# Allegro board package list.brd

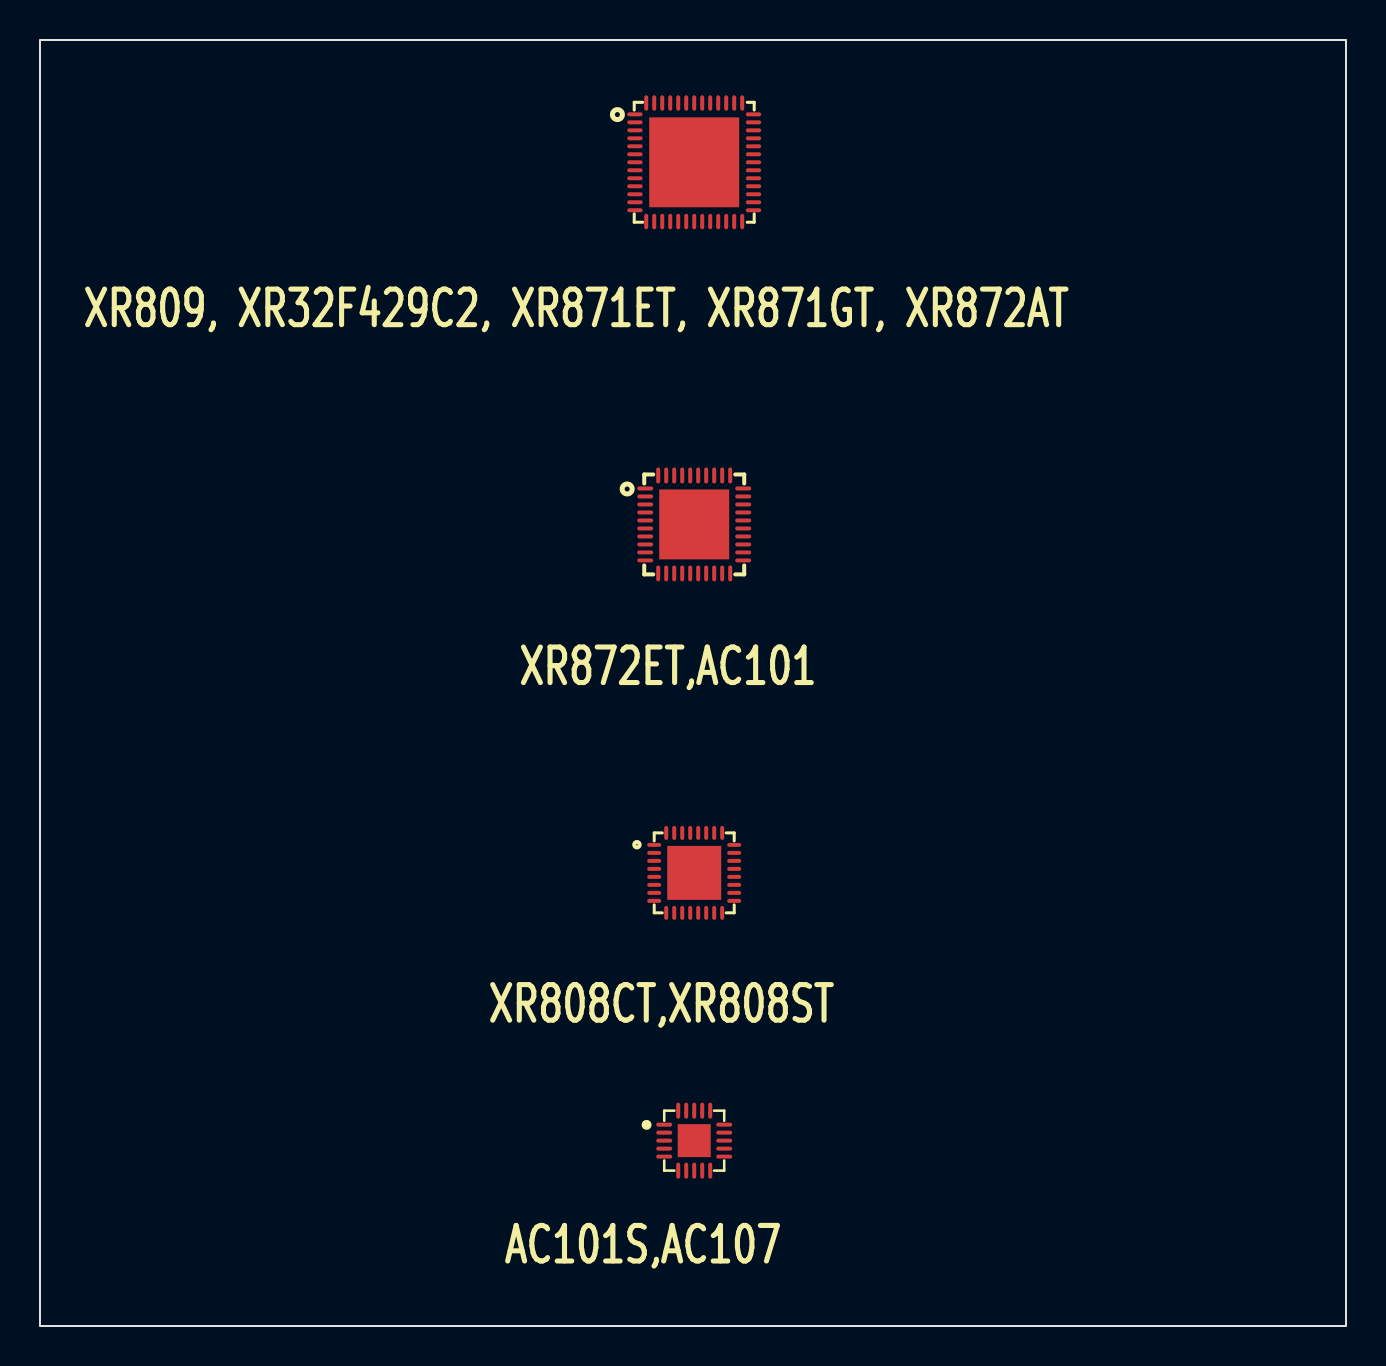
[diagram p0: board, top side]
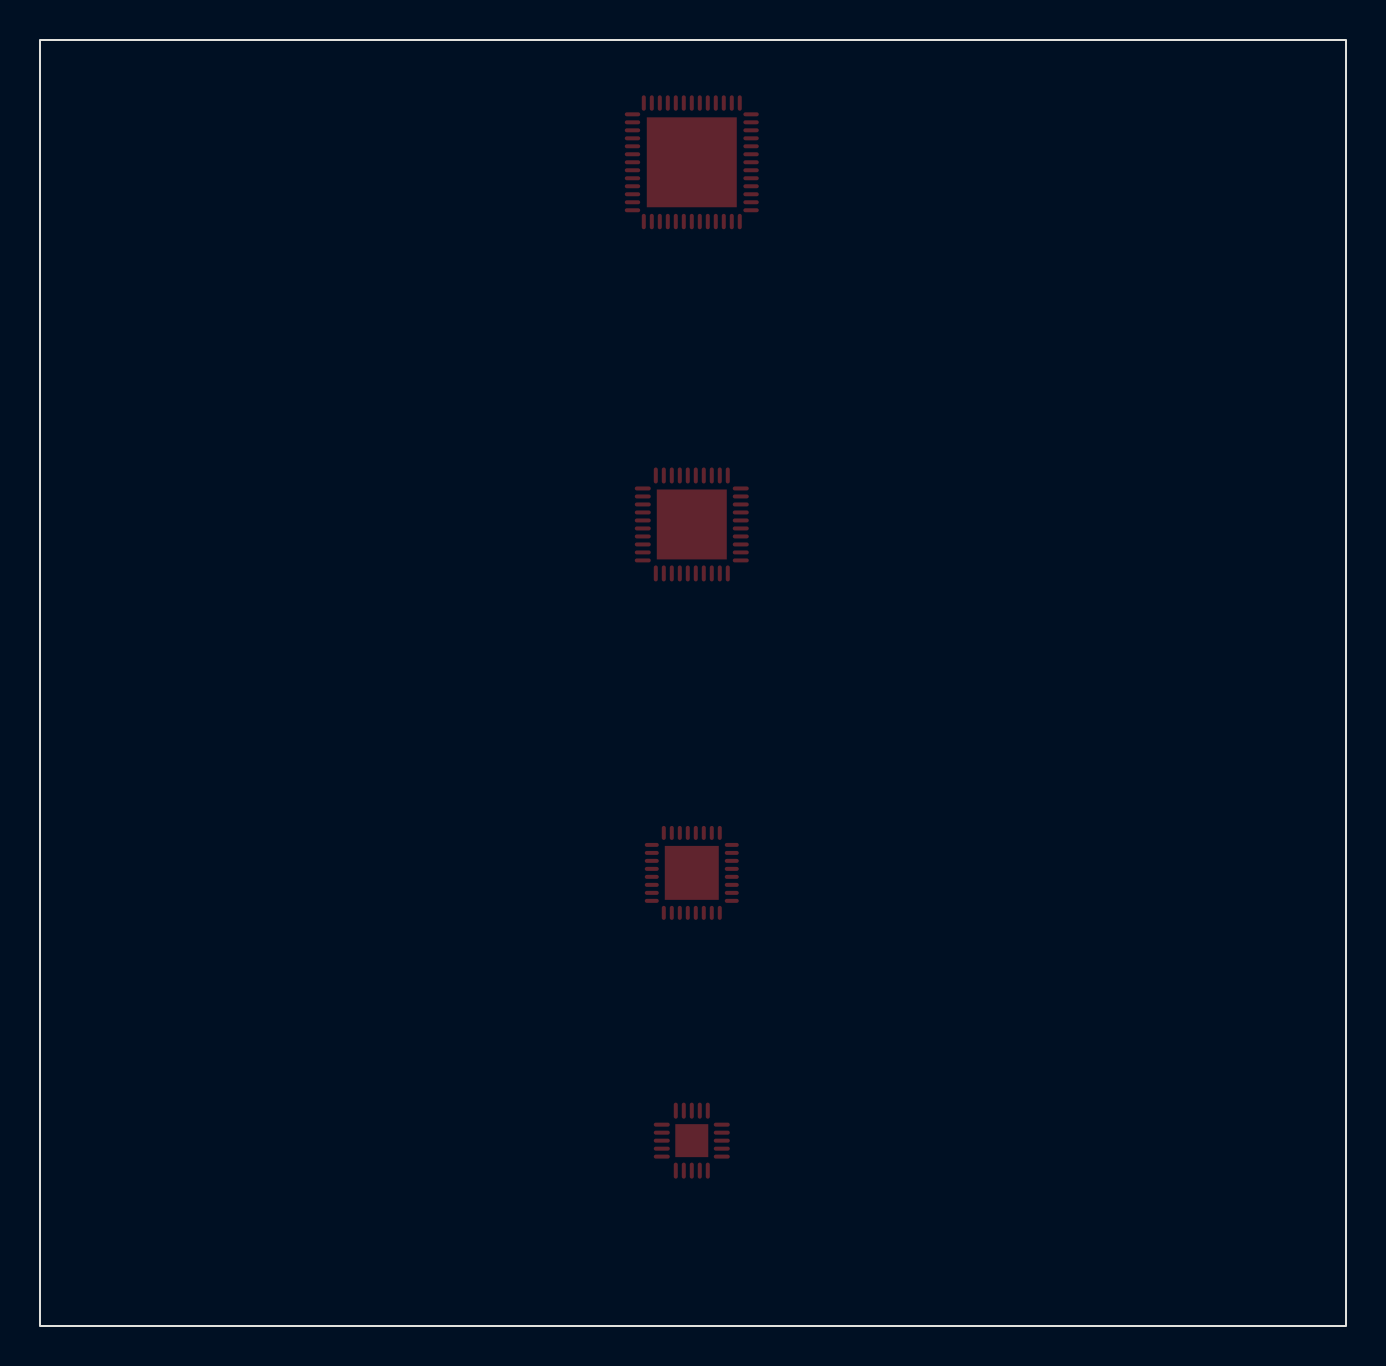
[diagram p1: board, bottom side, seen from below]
Outline 65.32 x 64.34 mm; copper layers: TOP, BOTTOM. Coordinates in mm from the lower left corner of the outline.
Outline path: rectangle 0,0 65.32,64.34

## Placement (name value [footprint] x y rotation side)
REF DES  VALUE  [unnamed]  32.72 22.67 0 top
REF DES#2  VALUE  [unnamed#2]  32.72 9.28 0 top
REF DES#3  VALUE  [unnamed#3]  32.72 40.1 0 top
REF DES#4  VALUE  [unnamed#4]  32.72 58.23 0 top

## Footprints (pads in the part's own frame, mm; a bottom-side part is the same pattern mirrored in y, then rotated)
unnamed
  oval 0.7x0.2 smd: 1(-2,1.4) 2(-2,1) 3(-2,0.6) 4(-2,0.2) 5(-2,-0.2) 6(-2,-0.6) 7(-2,-1) 8(-2,-1.4) 17(2,-1.4) 18(2,-1) 19(2,-0.6) 20(2,-0.2) 21(2,0.2) 22(2,0.6) 23(2,1) 24(2,1.4)
  oval 0.2x0.7 smd: 9(-1.4,-2) 10(-1,-2) 11(-0.6,-2) 12(-0.2,-2) 13(0.2,-2) 14(0.6,-2) 15(1,-2) 16(1.4,-2) 25(1.4,2) 26(1,2) 27(0.6,2) 28(0.2,2) 29(-0.2,2) 30(-0.6,2) 31(-1,2) 32(-1.4,2)
  rect 2.7x2.7 smd: 33(0,0)
unnamed#2
  custom 0.05x0.05 smd: 1(-1.5,0.8) 2(-1.5,0.4) 3(-1.5,0) 4(-1.5,-0.4) 5(-1.5,-0.8) 6(-0.8,-1.5) 7(-0.4,-1.5) 8(0,-1.5) 9(0.4,-1.5) 10(0.8,-1.5) 11(1.5,-0.8) 12(1.5,-0.4) 13(1.5,0) 14(1.5,0.4) 15(1.5,0.8) 16(0.8,1.5) 17(0.4,1.5) 18(0,1.5) 19(-0.4,1.5) 20(-0.8,1.5)
  rect 1.65x1.65 smd: 21(0,0)
unnamed#3
  oval 0.8x0.2 smd: 1(-2.45,1.8) 2(-2.45,1.4) 3(-2.45,1) 4(-2.45,0.6) 5(-2.45,0.2) 6(-2.45,-0.2) 7(-2.45,-0.6) 8(-2.45,-1) 9(-2.45,-1.4) 10(-2.45,-1.8) 21(2.45,-1.8) 22(2.45,-1.4) 23(2.45,-1) 24(2.45,-0.6) 25(2.45,-0.2) 26(2.45,0.2) 27(2.45,0.6) 28(2.45,1) 29(2.45,1.4) 30(2.45,1.8)
  oval 0.2x0.8 smd: 11(-1.8,-2.45) 12(-1.4,-2.45) 13(-1,-2.45) 14(-0.6,-2.45) 15(-0.2,-2.45) 16(0.2,-2.45) 17(0.6,-2.45) 18(1,-2.45) 19(1.4,-2.45) 20(1.8,-2.45) 31(1.8,2.45) 32(1.4,2.45) 33(1,2.45) 34(0.6,2.45) 35(0.2,2.45) 36(-0.2,2.45) 37(-0.6,2.45) 38(-1,2.45) 39(-1.4,2.45) 40(-1.8,2.45)
  rect 3.5x3.5 smd: 41(0,0)
unnamed#4
  oval 0.77x0.2 smd: 1(-2.965,2.4) 2(-2.965,2) 3(-2.965,1.6) 4(-2.965,1.2) 5(-2.965,0.8) 6(-2.965,0.4) 7(-2.965,0) 8(-2.965,-0.4) 9(-2.965,-0.8) 10(-2.965,-1.2) 11(-2.965,-1.6) 12(-2.965,-2) 13(-2.965,-2.4) 27(2.965,-2.4) 28(2.965,-2) 29(2.965,-1.6) 30(2.965,-1.2) 31(2.965,-0.8) 32(2.965,-0.4) 33(2.965,0) 34(2.965,0.4) 35(2.965,0.8) 36(2.965,1.2) 37(2.965,1.6) 38(2.965,2) 39(2.965,2.4)
  oval 0.2x0.77 smd: 14(-2.4,-2.965) 15(-2,-2.965) 16(-1.6,-2.965) 17(-1.2,-2.965) 18(-0.8,-2.965) 19(-0.4,-2.965) 20(0,-2.965) 21(0.4,-2.965) 22(0.8,-2.965) 23(1.2,-2.965) 24(1.6,-2.965) 25(2,-2.965) 26(2.4,-2.965) 40(2.4,2.965) 41(2,2.965) 42(1.6,2.965) 43(1.2,2.965) 44(0.8,2.965) 45(0.4,2.965) 46(0,2.965) 47(-0.4,2.965) 48(-0.8,2.965) 49(-1.2,2.965) 50(-1.6,2.965) 51(-2,2.965) 52(-2.4,2.965)
  rect 4.5x4.5 smd: 53(0,0)

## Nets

Pads without a net: REF DES 1 2 3 4 5 6 7 8 9 10 11 12 13 14 15 16 17 18 19 20 21 22 23 24 25 26 27 28 29 30 31 32 33; REF DES#2 1 2 3 4 5 6 7 8 9 10 11 12 13 14 15 16 17 18 19 20 21; REF DES#3 1 2 3 4 5 6 7 8 9 10 11 12 13 14 15 16 17 18 19 20 21 22 23 24 25 26 27 28 29 30 31 32 33 34 35 36 37 38 39 40 41; REF DES#4 1 2 3 4 5 6 7 8 9 10 11 12 13 14 15 16 17 18 19 20 21 22 23 24 25 26 27 28 29 30 31 32 33 34 35 36 37 38 39 40 41 42 43 44 45 46 47 48 49 50 51 52 53

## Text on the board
Ref Des/Silkscreen Top: XR809, XR32F429C2, XR871ET, XR871GT, XR872AT | XR808CT,XR808ST | AC101S,AC107 | XR872ET,AC101
